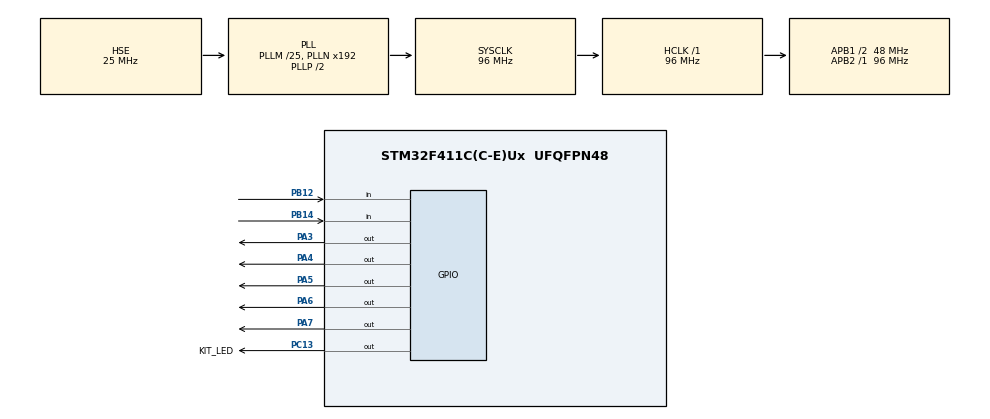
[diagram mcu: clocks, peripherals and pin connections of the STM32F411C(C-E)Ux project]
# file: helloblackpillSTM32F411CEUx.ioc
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Mcu.Family=STM32F4
Mcu.Name=STM32F411C(C-E)Ux
Mcu.Package=UFQFPN48
NVIC.PriorityGroup=NVIC_PRIORITYGROUP_4
NVIC.TIM4_IRQn=true\:0\:0\:false\:false\:true\:true\:true\:true
PA13.Mode=Serial_Wire
PA13.Signal=SYS_JTMS-SWDIO
PA14.Mode=Serial_Wire
PA14.Signal=SYS_JTCK-SWCLK
PA3.Signal=GPIO_Output
PA4.Signal=GPIO_Output
PA5.Signal=GPIO_Output
PA6.Signal=GPIO_Output
PA7.Signal=GPIO_Output
PB12.Signal=GPIO_Input
PB14.Signal=GPIO_Input
PC13-ANTI_TAMP.GPIO_Label=KIT_LED
PC13-ANTI_TAMP.Signal=GPIO_Output
PC14-OSC32_IN.Mode=LSE-External-Oscillator
PC14-OSC32_IN.Signal=RCC_OSC32_IN
PC15-OSC32_OUT.Mode=LSE-External-Oscillator
PC15-OSC32_OUT.Signal=RCC_OSC32_OUT
PH0\ -\ OSC_IN.Mode=HSE-External-Oscillator
PH0\ -\ OSC_IN.Signal=RCC_OSC_IN
PH1\ -\ OSC_OUT.Mode=HSE-External-Oscillator
PH1\ -\ OSC_OUT.Signal=RCC_OSC_OUT
ProjectManager.HeapSize=0x200
ProjectManager.StackSize=0x400
ProjectManager.TargetToolchain=Makefile
RCC.48MHZClocksFreq_Value=48000000
RCC.AHBFreq_Value=96000000
RCC.APB1CLKDivider=RCC_HCLK_DIV2
RCC.APB1Freq_Value=48000000
RCC.APB1TimFreq_Value=96000000
RCC.APB2Freq_Value=96000000
RCC.APB2TimFreq_Value=96000000
RCC.CortexFreq_Value=96000000
RCC.HCLKFreq_Value=96000000
RCC.HSE_VALUE=25000000
RCC.HSI_VALUE=16000000
RCC.PLLM=25
RCC.PLLSourceVirtual=RCC_PLLSOURCE_HSE
RCC.SYSCLKFreq_VALUE=96000000
RCC.SYSCLKSource=RCC_SYSCLKSOURCE_PLLCLK
RCC.VCOOutputFreq_Value=192000000
TIM4.Period=1030
TIM4.Prescaler=9600-1
VP_TIM4_VS_ClockSourceINT.Mode=Internal
board=custom

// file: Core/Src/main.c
/* USER CODE BEGIN Header */
/**
  ******************************************************************************
  * @file           : main.c
  * @brief          : Main program body
  ******************************************************************************
  * @attention
  *
  * Copyright (c) 2022 STMicroelectronics.
  * All rights reserved.
  *
  * This software is licensed under terms that can be found in the LICENSE file
  * in the root directory of this software component.
  * If no LICENSE file comes with this software, it is provided AS-IS.
  *
  ******************************************************************************
  */
/* USER CODE END Header */
#include "main.h"
#include "button.h"

TIM_HandleTypeDef htim4;

/* USER CODE BEGIN PV */
uint32_t gDec=1030;
uint8_t gLeds=0;
/* USER CODE END PV */

void SystemClock_Config(void);
static void MX_GPIO_Init(void);
static void MX_TIM4_Init(void);

int main(void)
{

  /* MCU Configuration--------------------------------------------------------*/

  /* Reset of all peripherals, Initializes the Flash interface and the Systick. */
  HAL_Init();

  /* USER CODE BEGIN Init */
  uint8_t i = 0;

  /* USER CODE END Init */

  /* Configure the system clock */
  SystemClock_Config();

  /* Initialize all configured peripherals */
  MX_GPIO_Init();
  MX_TIM4_Init();
  /* USER CODE BEGIN 2 */
  HAL_TIM_Base_Start_IT(&htim4);

  /* USER CODE END 2 */

  /* Infinite loop */
  /* USER CODE BEGIN WHILE */
  while(1)
  {
    for(i=0;i<10;i++){
      if (button_release(GPIOB, GPIO_PIN_14, 1))
      {

        if (gDec < 65535 - 1030)
        {
          gDec = gDec + 1030; //aumenta o período do timer
          MX_TIM4_Init();
        }else{
          gDec = 1030; //reseta o timer
        }
      }else if (!button_release(GPIOB, GPIO_PIN_12, 1))
      {
        if (gDec > 1030)
        {
          gDec = gDec - 1030; //diminiu o período do timer
          MX_TIM4_Init();
        }
      } else{
      HAL_Delay(200);
      HAL_GPIO_TogglePin(KIT_LED_GPIO_Port, KIT_LED_Pin);
    }

    }

    /* USER CODE END WHILE */

  }
}

void SystemClock_Config(void)
{
  RCC_OscInitTypeDef RCC_OscInitStruct = {0};
  RCC_ClkInitTypeDef RCC_ClkInitStruct = {0};

  /** Configure the main internal regulator output voltage
  */
  __HAL_RCC_PWR_CLK_ENABLE();
  __HAL_PWR_VOLTAGESCALING_CONFIG(PWR_REGULATOR_VOLTAGE_SCALE1);

  /** Initializes the RCC Oscillators according to the specified parameters
  * in the RCC_OscInitTypeDef structure.
  */
  RCC_OscInitStruct.OscillatorType = RCC_OSCILLATORTYPE_HSE;
  RCC_OscInitStruct.HSEState = RCC_HSE_ON;
  RCC_OscInitStruct.PLL.PLLState = RCC_PLL_ON;
  RCC_OscInitStruct.PLL.PLLSource = RCC_PLLSOURCE_HSE;
  RCC_OscInitStruct.PLL.PLLM = 25;
  RCC_OscInitStruct.PLL.PLLN = 192;
  RCC_OscInitStruct.PLL.PLLP = RCC_PLLP_DIV2;
  RCC_OscInitStruct.PLL.PLLQ = 4;
  if (HAL_RCC_OscConfig(&RCC_OscInitStruct) != HAL_OK)
  {
    Error_Handler();
  }

  /** Initializes the CPU, AHB and APB buses clocks
  */
  RCC_ClkInitStruct.ClockType = RCC_CLOCKTYPE_HCLK|RCC_CLOCKTYPE_SYSCLK
                              |RCC_CLOCKTYPE_PCLK1|RCC_CLOCKTYPE_PCLK2;
  RCC_ClkInitStruct.SYSCLKSource = RCC_SYSCLKSOURCE_PLLCLK;
  RCC_ClkInitStruct.AHBCLKDivider = RCC_SYSCLK_DIV1;
  RCC_ClkInitStruct.APB1CLKDivider = RCC_HCLK_DIV2;
  RCC_ClkInitStruct.APB2CLKDivider = RCC_HCLK_DIV1;

  if (HAL_RCC_ClockConfig(&RCC_ClkInitStruct, FLASH_LATENCY_3) != HAL_OK)
  {
    Error_Handler();
  }
}

static void MX_TIM4_Init(void)
{

  TIM_ClockConfigTypeDef sClockSourceConfig = {0};
  TIM_MasterConfigTypeDef sMasterConfig = {0};

  htim4.Instance = TIM4;
  htim4.Init.Prescaler = 9600-1;
  htim4.Init.CounterMode = TIM_COUNTERMODE_UP;
  htim4.Init.Period = gDec;
  htim4.Init.ClockDivision = TIM_CLOCKDIVISION_DIV1;
  htim4.Init.AutoReloadPreload = TIM_AUTORELOAD_PRELOAD_DISABLE;
  if (HAL_TIM_Base_Init(&htim4) != HAL_OK)
  {
    Error_Handler();
  }
  sClockSourceConfig.ClockSource = TIM_CLOCKSOURCE_INTERNAL;
  if (HAL_TIM_ConfigClockSource(&htim4, &sClockSourceConfig) != HAL_OK)
  {
    Error_Handler();
  }
  sMasterConfig.MasterOutputTrigger = TIM_TRGO_RESET;
  sMasterConfig.MasterSlaveMode = TIM_MASTERSLAVEMODE_DISABLE;
  if (HAL_TIMEx_MasterConfigSynchronization(&htim4, &sMasterConfig) != HAL_OK)
  {
    Error_Handler();
  }

}

static void MX_GPIO_Init(void)
{
  GPIO_InitTypeDef GPIO_InitStruct = {0};

  /* GPIO Ports Clock Enable */
  __HAL_RCC_GPIOC_CLK_ENABLE();
  __HAL_RCC_GPIOH_CLK_ENABLE();
  __HAL_RCC_GPIOA_CLK_ENABLE();
  __HAL_RCC_GPIOB_CLK_ENABLE();

  /*Configure GPIO pin Output Level */
  HAL_GPIO_WritePin(KIT_LED_GPIO_Port, KIT_LED_Pin, GPIO_PIN_RESET);

  /*Configure GPIO pin Output Level */
  HAL_GPIO_WritePin(GPIOA, GPIO_PIN_3|GPIO_PIN_4|GPIO_PIN_5|GPIO_PIN_6
                          |GPIO_PIN_7, GPIO_PIN_RESET);

  /*Configure GPIO pin : KIT_LED_Pin */
  GPIO_InitStruct.Pin = KIT_LED_Pin;
  GPIO_InitStruct.Mode = GPIO_MODE_OUTPUT_PP;
  GPIO_InitStruct.Pull = GPIO_NOPULL;
  GPIO_InitStruct.Speed = GPIO_SPEED_FREQ_LOW;
  HAL_GPIO_Init(KIT_LED_GPIO_Port, &GPIO_InitStruct);

  /*Configure GPIO pins : PA3 PA4 PA5 PA6
                           PA7 */
  GPIO_InitStruct.Pin = GPIO_PIN_3|GPIO_PIN_4|GPIO_PIN_5|GPIO_PIN_6
                          |GPIO_PIN_7;
  GPIO_InitStruct.Mode = GPIO_MODE_OUTPUT_PP;
  GPIO_InitStruct.Pull = GPIO_NOPULL;
  GPIO_InitStruct.Speed = GPIO_SPEED_FREQ_LOW;
  HAL_GPIO_Init(GPIOA, &GPIO_InitStruct);

  /*Configure GPIO pins : PB4 PB5 */
  GPIO_InitStruct.Pin = GPIO_PIN_4|GPIO_PIN_5;
  GPIO_InitStruct.Mode = GPIO_MODE_INPUT;
  GPIO_InitStruct.Pull = GPIO_NOPULL;
  HAL_GPIO_Init(GPIOB, &GPIO_InitStruct);

}

/* USER CODE BEGIN 4 */
void HAL_TIM_PeriodElapsedCallback(TIM_HandleTypeDef *htim)
{

  if (gLeds==0)
  {
    gLeds = 32; //reinicia o contador (32= 2^5, padrão para 5 bits)
  }
  gLeds--;
  HAL_GPIO_WritePin(GPIOA, gLeds << 3, 1); //acende Leds conforme o valor de gLeds
  HAL_GPIO_WritePin(GPIOA, (~gLeds) << 3, 0); //Apaga os LEDs restantes
}
/* USER CODE END 4 */

void Error_Handler(void)
{
  __disable_irq();
  while (1)
  {
  }
}
